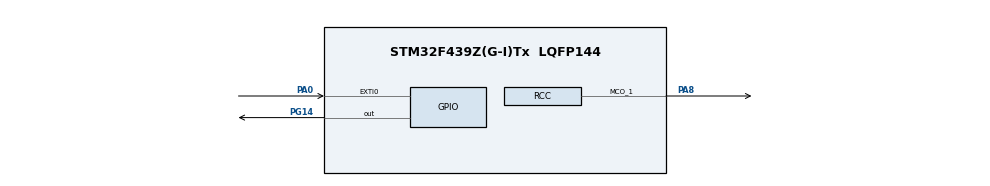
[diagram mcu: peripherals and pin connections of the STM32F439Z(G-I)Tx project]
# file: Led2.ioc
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Mcu.Family=STM32F4
Mcu.Name=STM32F439Z(G-I)Tx
Mcu.Package=LQFP144
NVIC.EXTI0_IRQn=true\:0\:0\:false\:false\:true
NVIC.PriorityGroup=NVIC_PRIORITYGROUP_4
PA0/WKUP.Signal=GPXTI0
PA13.Mode=Serial_Wire
PA13.Signal=SYS_JTMS-SWDIO
PA14.Mode=Serial_Wire
PA14.Signal=SYS_JTCK-SWCLK
PA8.Mode=Clock-out-1
PA8.Signal=RCC_MCO_1
PC14/OSC32_IN.Mode=LSE-External-Oscillator
PC14/OSC32_IN.Signal=RCC_OSC32_IN
PC15/OSC32_OUT.Mode=LSE-External-Oscillator
PC15/OSC32_OUT.Signal=RCC_OSC32_OUT
PG14.Signal=GPIO_Output
PH0/OSC_IN.Mode=HSE-External-Oscillator
PH0/OSC_IN.Signal=RCC_OSC_IN
PH1/OSC_OUT.Mode=HSE-External-Oscillator
PH1/OSC_OUT.Signal=RCC_OSC_OUT
ProjectManager.HeapSize=0x200
ProjectManager.StackSize=0x400
ProjectManager.TargetToolchain=EWARM
RCC.48MHZClocksFreq_Value=45000000
RCC.AHBFreq_Value=180000000
RCC.APB1CLKDivider=RCC_HCLK_DIV4
RCC.APB1Freq_Value=45000000
RCC.APB1TimFreq_Value=90000000
RCC.APB2CLKDivider=RCC_HCLK_DIV2
RCC.APB2Freq_Value=90000000
RCC.APB2TimFreq_Value=180000000
RCC.CortexFreq_Value=22500000
RCC.Cortex_Div=SYSTICK_CLKSOURCE_HCLK_DIV8
RCC.HCLKFreq_Value=180000000
RCC.HSE_VALUE=8000000
RCC.HSI_VALUE=16000000
RCC.PLLM=8
RCC.PLLN=360
RCC.PLLQ=8
RCC.SYSCLKFreq_VALUE=180000000
RCC.SYSCLKSource=RCC_SYSCLKSOURCE_PLLCLK
RCC.VCOOutputFreq_Value=360000000
VP_RTC_VS_RTC_Activate.Mode=RTC_Enabled
VP_RTC_VS_RTC_Calendar.Mode=RTC_Calendar
VP_RTC_VS_RTC_WakeUp_intern.Mode=WakeUp
board=Led2

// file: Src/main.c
/**
  ******************************************************************************
  * File Name          : main.c
  * Description        : Main program body
  ******************************************************************************
  ** This notice applies to any and all portions of this file
  * that are not between comment pairs USER CODE BEGIN and
  * USER CODE END. Other portions of this file, whether
  * inserted by the user or by software development tools
  * are owned by their respective copyright owners.
  *
  * COPYRIGHT(c) 2017 STMicroelectronics
  *
  * Redistribution and use in source and binary forms, with or without modification,
  * are permitted provided that the following conditions are met:
  *   1. Redistributions of source code must retain the above copyright notice,
  *      this list of conditions and the following disclaimer.
  *   2. Redistributions in binary form must reproduce the above copyright notice,
  *      this list of conditions and the following disclaimer in the documentation
  *      and/or other materials provided with the distribution.
  *   3. Neither the name of STMicroelectronics nor the names of its contributors
  *      may be used to endorse or promote products derived from this software
  *      without specific prior written permission.
  *
  * THIS SOFTWARE IS PROVIDED BY THE COPYRIGHT HOLDERS AND CONTRIBUTORS "AS IS"
  * AND ANY EXPRESS OR IMPLIED WARRANTIES, INCLUDING, BUT NOT LIMITED TO, THE
  * IMPLIED WARRANTIES OF MERCHANTABILITY AND FITNESS FOR A PARTICULAR PURPOSE ARE
  * DISCLAIMED. IN NO EVENT SHALL THE COPYRIGHT HOLDER OR CONTRIBUTORS BE LIABLE
  * FOR ANY DIRECT, INDIRECT, INCIDENTAL, SPECIAL, EXEMPLARY, OR CONSEQUENTIAL
  * DAMAGES (INCLUDING, BUT NOT LIMITED TO, PROCUREMENT OF SUBSTITUTE GOODS OR
  * SERVICES; LOSS OF USE, DATA, OR PROFITS; OR BUSINESS INTERRUPTION) HOWEVER
  * CAUSED AND ON ANY THEORY OF LIABILITY, WHETHER IN CONTRACT, STRICT LIABILITY,
  * OR TORT (INCLUDING NEGLIGENCE OR OTHERWISE) ARISING IN ANY WAY OUT OF THE USE
  * OF THIS SOFTWARE, EVEN IF ADVISED OF THE POSSIBILITY OF SUCH DAMAGE.
  *
  ******************************************************************************
  */
#include "main.h"
#include "stm32f4xx_hal.h"

RTC_HandleTypeDef hrtc;

/* USER CODE BEGIN PV */
/* Private variables ---------------------------------------------------------*/

/* USER CODE END PV */

void SystemClock_Config(void);
static void MX_GPIO_Init(void);
static void MX_RTC_Init(void);

/* USER CODE BEGIN PFP */
/* Private function prototypes -----------------------------------------------*/

/* USER CODE END PFP */

int main(void)
{

  /* MCU Configuration----------------------------------------------------------*/

  /* Reset of all peripherals, Initializes the Flash interface and the Systick. */
  HAL_Init();

  /* Configure the system clock */
  SystemClock_Config();

  /* Initialize all configured peripherals */
  MX_GPIO_Init();
  MX_RTC_Init();

  /* Infinite loop */
  while (1)
  {

  }

}

/** System Clock Configuration
*/
void SystemClock_Config(void)
{

  RCC_OscInitTypeDef RCC_OscInitStruct;
  RCC_ClkInitTypeDef RCC_ClkInitStruct;
  RCC_PeriphCLKInitTypeDef PeriphClkInitStruct;

    /**Configure the main internal regulator output voltage
    */
  __HAL_RCC_PWR_CLK_ENABLE();

  __HAL_PWR_VOLTAGESCALING_CONFIG(PWR_REGULATOR_VOLTAGE_SCALE1);

    /**Initializes the CPU, AHB and APB busses clocks
    */
  RCC_OscInitStruct.OscillatorType = RCC_OSCILLATORTYPE_HSI|RCC_OSCILLATORTYPE_LSI;
  RCC_OscInitStruct.HSIState = RCC_HSI_ON;
  RCC_OscInitStruct.HSICalibrationValue = 16;
  RCC_OscInitStruct.LSIState = RCC_LSI_ON;
  RCC_OscInitStruct.PLL.PLLState = RCC_PLL_ON;
  RCC_OscInitStruct.PLL.PLLSource = RCC_PLLSOURCE_HSI;
  RCC_OscInitStruct.PLL.PLLM = 8;
  RCC_OscInitStruct.PLL.PLLN = 360;
  RCC_OscInitStruct.PLL.PLLP = RCC_PLLP_DIV2;
  RCC_OscInitStruct.PLL.PLLQ = 8;
  if (HAL_RCC_OscConfig(&RCC_OscInitStruct) != HAL_OK)
  {
    _Error_Handler(__FILE__, __LINE__);
  }

    /**Activate the Over-Drive mode
    */
  if (HAL_PWREx_EnableOverDrive() != HAL_OK)
  {
    _Error_Handler(__FILE__, __LINE__);
  }

    /**Initializes the CPU, AHB and APB busses clocks
    */
  RCC_ClkInitStruct.ClockType = RCC_CLOCKTYPE_HCLK|RCC_CLOCKTYPE_SYSCLK
                              |RCC_CLOCKTYPE_PCLK1|RCC_CLOCKTYPE_PCLK2;
  RCC_ClkInitStruct.SYSCLKSource = RCC_SYSCLKSOURCE_PLLCLK;
  RCC_ClkInitStruct.AHBCLKDivider = RCC_SYSCLK_DIV1;
  RCC_ClkInitStruct.APB1CLKDivider = RCC_HCLK_DIV4;
  RCC_ClkInitStruct.APB2CLKDivider = RCC_HCLK_DIV2;

  if (HAL_RCC_ClockConfig(&RCC_ClkInitStruct, FLASH_LATENCY_5) != HAL_OK)
  {
    _Error_Handler(__FILE__, __LINE__);
  }

  PeriphClkInitStruct.PeriphClockSelection = RCC_PERIPHCLK_RTC;
  PeriphClkInitStruct.RTCClockSelection = RCC_RTCCLKSOURCE_LSI;
  if (HAL_RCCEx_PeriphCLKConfig(&PeriphClkInitStruct) != HAL_OK)
  {
    _Error_Handler(__FILE__, __LINE__);
  }

  HAL_RCC_MCOConfig(RCC_MCO1, RCC_MCO1SOURCE_HSI, RCC_MCODIV_1);

    /**Configure the Systick interrupt time
    */
  HAL_SYSTICK_Config(HAL_RCC_GetHCLKFreq()/8000);

    /**Configure the Systick
    */
  HAL_SYSTICK_CLKSourceConfig(SYSTICK_CLKSOURCE_HCLK_DIV8);

  /* SysTick_IRQn interrupt configuration */
  HAL_NVIC_SetPriority(SysTick_IRQn, 0, 0);
}

/* RTC init function */
static void MX_RTC_Init(void)
{

  RTC_TimeTypeDef sTime;
  RTC_DateTypeDef sDate;

    /**Initialize RTC Only
    */
  hrtc.Instance = RTC;
  hrtc.Init.HourFormat = RTC_HOURFORMAT_24;
  hrtc.Init.AsynchPrediv = 127;
  hrtc.Init.SynchPrediv = 255;
  hrtc.Init.OutPut = RTC_OUTPUT_DISABLE;
  hrtc.Init.OutPutPolarity = RTC_OUTPUT_POLARITY_HIGH;
  hrtc.Init.OutPutType = RTC_OUTPUT_TYPE_OPENDRAIN;
  if (HAL_RTC_Init(&hrtc) != HAL_OK)
  {
    _Error_Handler(__FILE__, __LINE__);
  }

    /**Initialize RTC and set the Time and Date
    */
  if(HAL_RTCEx_BKUPRead(&hrtc, RTC_BKP_DR0) != 0x32F2){
  sTime.Hours = 0x0;
  sTime.Minutes = 0x0;
  sTime.Seconds = 0x0;
  sTime.DayLightSaving = RTC_DAYLIGHTSAVING_NONE;
  sTime.StoreOperation = RTC_STOREOPERATION_RESET;
  if (HAL_RTC_SetTime(&hrtc, &sTime, RTC_FORMAT_BCD) != HAL_OK)
  {
    _Error_Handler(__FILE__, __LINE__);
  }

  sDate.WeekDay = RTC_WEEKDAY_MONDAY;
  sDate.Month = RTC_MONTH_JANUARY;
  sDate.Date = 0x1;
  sDate.Year = 0x0;

  if (HAL_RTC_SetDate(&hrtc, &sDate, RTC_FORMAT_BCD) != HAL_OK)
  {
    _Error_Handler(__FILE__, __LINE__);
  }

    HAL_RTCEx_BKUPWrite(&hrtc,RTC_BKP_DR0,0x32F2);
  }
    /**Enable the WakeUp
    */
  if (HAL_RTCEx_SetWakeUpTimer(&hrtc, 0, RTC_WAKEUPCLOCK_RTCCLK_DIV16) != HAL_OK)
  {
    _Error_Handler(__FILE__, __LINE__);
  }

}

/** Configure pins as
        * Analog
        * Input
        * Output
        * EVENT_OUT
        * EXTI
        * Free pins are configured automatically as Analog (this feature is enabled through
        * the Code Generation settings)
     PA8   ------> RCC_MCO_1
*/
static void MX_GPIO_Init(void)
{

  GPIO_InitTypeDef GPIO_InitStruct;

  /* GPIO Ports Clock Enable */
  __HAL_RCC_GPIOE_CLK_ENABLE();
  __HAL_RCC_GPIOC_CLK_ENABLE();
  __HAL_RCC_GPIOF_CLK_ENABLE();
  __HAL_RCC_GPIOH_CLK_ENABLE();
  __HAL_RCC_GPIOA_CLK_ENABLE();
  __HAL_RCC_GPIOB_CLK_ENABLE();
  __HAL_RCC_GPIOG_CLK_ENABLE();
  __HAL_RCC_GPIOD_CLK_ENABLE();

  /*Configure GPIO pin Output Level */
  HAL_GPIO_WritePin(GPIOG, GPIO_PIN_14, GPIO_PIN_RESET);

  /*Configure GPIO pins : PE2 PE3 PE4 PE5
                           PE6 PE7 PE8 PE9
                           PE10 PE11 PE12 PE13
                           PE14 PE15 PE0 PE1 */
  GPIO_InitStruct.Pin = GPIO_PIN_2|GPIO_PIN_3|GPIO_PIN_4|GPIO_PIN_5
                          |GPIO_PIN_6|GPIO_PIN_7|GPIO_PIN_8|GPIO_PIN_9
                          |GPIO_PIN_10|GPIO_PIN_11|GPIO_PIN_12|GPIO_PIN_13
                          |GPIO_PIN_14|GPIO_PIN_15|GPIO_PIN_0|GPIO_PIN_1;
  GPIO_InitStruct.Mode = GPIO_MODE_ANALOG;
  GPIO_InitStruct.Pull = GPIO_NOPULL;
  HAL_GPIO_Init(GPIOE, &GPIO_InitStruct);

  /*Configure GPIO pins : PC13 PC0 PC1 PC2
                           PC3 PC4 PC5 PC6
                           PC7 PC8 PC9 PC10
                           PC11 PC12 */
  GPIO_InitStruct.Pin = GPIO_PIN_13|GPIO_PIN_0|GPIO_PIN_1|GPIO_PIN_2
                          |GPIO_PIN_3|GPIO_PIN_4|GPIO_PIN_5|GPIO_PIN_6
                          |GPIO_PIN_7|GPIO_PIN_8|GPIO_PIN_9|GPIO_PIN_10
                          |GPIO_PIN_11|GPIO_PIN_12;
  GPIO_InitStruct.Mode = GPIO_MODE_ANALOG;
  GPIO_InitStruct.Pull = GPIO_NOPULL;
  HAL_GPIO_Init(GPIOC, &GPIO_InitStruct);

  /*Configure GPIO pins : PF0 PF1 PF2 PF3
                           PF4 PF5 PF6 PF7
                           PF8 PF9 PF10 PF11
                           PF12 PF13 PF14 PF15 */
  GPIO_InitStruct.Pin = GPIO_PIN_0|GPIO_PIN_1|GPIO_PIN_2|GPIO_PIN_3
                          |GPIO_PIN_4|GPIO_PIN_5|GPIO_PIN_6|GPIO_PIN_7
                          |GPIO_PIN_8|GPIO_PIN_9|GPIO_PIN_10|GPIO_PIN_11
                          |GPIO_PIN_12|GPIO_PIN_13|GPIO_PIN_14|GPIO_PIN_15;
  GPIO_InitStruct.Mode = GPIO_MODE_ANALOG;
  GPIO_InitStruct.Pull = GPIO_NOPULL;
  HAL_GPIO_Init(GPIOF, &GPIO_InitStruct);

  /*Configure GPIO pin : PA0 */
  GPIO_InitStruct.Pin = GPIO_PIN_0;
  GPIO_InitStruct.Mode = GPIO_MODE_IT_RISING;
  GPIO_InitStruct.Pull = GPIO_NOPULL;
  HAL_GPIO_Init(GPIOA, &GPIO_InitStruct);

  /*Configure GPIO pins : PA1 PA2 PA3 PA4
                           PA5 PA6 PA7 PA9
                           PA10 PA11 PA12 PA15 */
  GPIO_InitStruct.Pin = GPIO_PIN_1|GPIO_PIN_2|GPIO_PIN_3|GPIO_PIN_4
                          |GPIO_PIN_5|GPIO_PIN_6|GPIO_PIN_7|GPIO_PIN_9
                          |GPIO_PIN_10|GPIO_PIN_11|GPIO_PIN_12|GPIO_PIN_15;
  GPIO_InitStruct.Mode = GPIO_MODE_ANALOG;
  GPIO_InitStruct.Pull = GPIO_NOPULL;
  HAL_GPIO_Init(GPIOA, &GPIO_InitStruct);

  /*Configure GPIO pins : PB0 PB1 PB2 PB10
                           PB11 PB12 PB13 PB14
                           PB15 PB3 PB4 PB5
                           PB6 PB7 PB8 PB9 */
  GPIO_InitStruct.Pin = GPIO_PIN_0|GPIO_PIN_1|GPIO_PIN_2|GPIO_PIN_10
                          |GPIO_PIN_11|GPIO_PIN_12|GPIO_PIN_13|GPIO_PIN_14
                          |GPIO_PIN_15|GPIO_PIN_3|GPIO_PIN_4|GPIO_PIN_5
                          |GPIO_PIN_6|GPIO_PIN_7|GPIO_PIN_8|GPIO_PIN_9;
  GPIO_InitStruct.Mode = GPIO_MODE_ANALOG;
  GPIO_InitStruct.Pull = GPIO_NOPULL;
  HAL_GPIO_Init(GPIOB, &GPIO_InitStruct);

  /*Configure GPIO pins : PG0 PG1 PG2 PG3
                           PG4 PG5 PG6 PG7
                           PG8 PG9 PG10 PG11
                           PG12 PG13 PG15 */
  GPIO_InitStruct.Pin = GPIO_PIN_0|GPIO_PIN_1|GPIO_PIN_2|GPIO_PIN_3
                          |GPIO_PIN_4|GPIO_PIN_5|GPIO_PIN_6|GPIO_PIN_7
                          |GPIO_PIN_8|GPIO_PIN_9|GPIO_PIN_10|GPIO_PIN_11
                          |GPIO_PIN_12|GPIO_PIN_13|GPIO_PIN_15;
  GPIO_InitStruct.Mode = GPIO_MODE_ANALOG;
  GPIO_InitStruct.Pull = GPIO_NOPULL;
  HAL_GPIO_Init(GPIOG, &GPIO_InitStruct);

  /*Configure GPIO pins : PD8 PD9 PD10 PD11
                           PD12 PD13 PD14 PD15
                           PD0 PD1 PD2 PD3
                           PD4 PD5 PD6 PD7 */
  GPIO_InitStruct.Pin = GPIO_PIN_8|GPIO_PIN_9|GPIO_PIN_10|GPIO_PIN_11
                          |GPIO_PIN_12|GPIO_PIN_13|GPIO_PIN_14|GPIO_PIN_15
                          |GPIO_PIN_0|GPIO_PIN_1|GPIO_PIN_2|GPIO_PIN_3
                          |GPIO_PIN_4|GPIO_PIN_5|GPIO_PIN_6|GPIO_PIN_7;
  GPIO_InitStruct.Mode = GPIO_MODE_ANALOG;
  GPIO_InitStruct.Pull = GPIO_NOPULL;
  HAL_GPIO_Init(GPIOD, &GPIO_InitStruct);

  /*Configure GPIO pin : PA8 */
  GPIO_InitStruct.Pin = GPIO_PIN_8;
  GPIO_InitStruct.Mode = GPIO_MODE_AF_PP;
  GPIO_InitStruct.Pull = GPIO_NOPULL;
  GPIO_InitStruct.Speed = GPIO_SPEED_FREQ_LOW;
  GPIO_InitStruct.Alternate = GPIO_AF0_MCO;
  HAL_GPIO_Init(GPIOA, &GPIO_InitStruct);

  /*Configure GPIO pin : PG14 */
  GPIO_InitStruct.Pin = GPIO_PIN_14;
  GPIO_InitStruct.Mode = GPIO_MODE_OUTPUT_PP;
  GPIO_InitStruct.Pull = GPIO_NOPULL;
  GPIO_InitStruct.Speed = GPIO_SPEED_FREQ_LOW;
  HAL_GPIO_Init(GPIOG, &GPIO_InitStruct);

  /* EXTI interrupt init*/
  HAL_NVIC_SetPriority(EXTI0_IRQn, 0, 0);
  HAL_NVIC_EnableIRQ(EXTI0_IRQn);

}

/* USER CODE BEGIN 4 */
void HAL_GPIO_EXTI_Callback(uint16_t GPIO_Pin)
{
if(GPIO_Pin == GPIO_PIN_0) {
HAL_GPIO_WritePin(GPIOG, GPIO_PIN_14, GPIO_PIN_SET);
} else {
__NOP();
}
}
/* USER CODE END 4 */

void _Error_Handler(char * file, int line)
{
  while(1)
  {
  }
}

/************************ (C) COPYRIGHT STMicroelectronics *****END OF FILE****/
